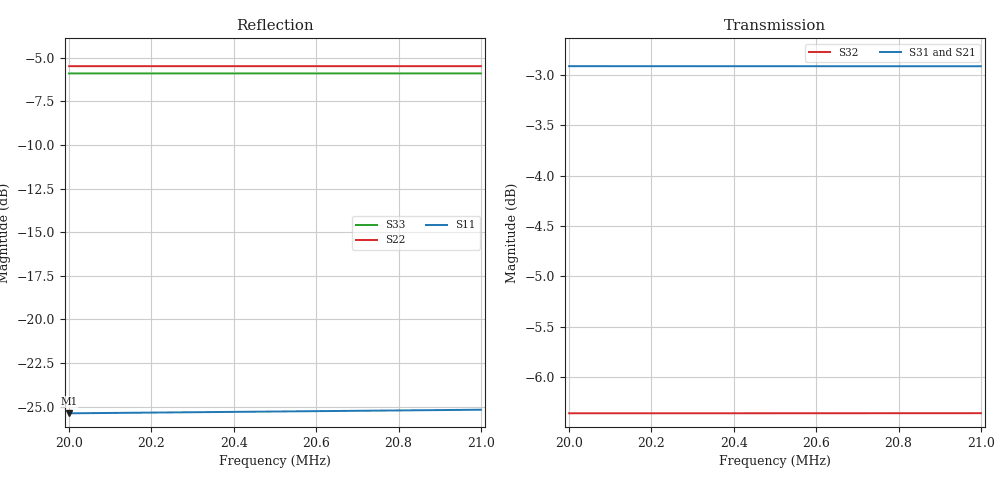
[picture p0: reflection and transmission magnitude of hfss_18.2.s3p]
! Touchstone file exported from HFSS 2018.2.0
!  File:  test.aedt
!  Generated:  4:09:18  mai 02, 2019
!  Design:  test
!  Project:  test
!  Setup:  Setup1
!  Solution:  Sweep
!Data is not renormalized
# GHZ S MA
! Modal data exported
! Port[1] = 1:1
! Port[2] = 2:1
! Port[3] = 3:1
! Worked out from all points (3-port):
!   11 points, 20 MHz to 21 MHz, reference per port
!   strongest paths, dB at 20 MHz, 20.2 MHz, 20.5 MHz, 20.8 MHz, 21 MHz:
!     S31: -2.9, -2.9, -2.9, -2.9, -2.9
!     S21: -3.1, -3.1, -3.1, -3.1, -3.1
!     S32: -6.4, -6.4, -6.4, -6.4, -6.4
!   lowest |S11| = -25.4 dB at 20 MHz (marker M1), VSWR 1.11
!   |S11| at or under -10 dB: start of sweep to end of sweep
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0.02  0.0538 -57.1  0.6968 -9.9  0.7151 -10.1
      0.6968 -9.9  0.5321 175.3  0.4808 -9.1
      0.7151 -10.1  0.4808 -9.1  0.5073 175.2
0.0201  0.05393 -57.4  0.6968 -9.9  0.7151 -10.1
        0.6968 -9.9  0.5321 175.3  0.4808 -9.2
        0.7151 -10.1  0.4808 -9.2  0.5073 175.1
0.0202  0.05406 -57.6  0.6968 -10.0  0.7151 -10.2
        0.6968 -10.0  0.5321 175.3  0.4808 -9.2
        0.7151 -10.2  0.4808 -9.2  0.5073 175.1
0.0203  0.05419 -57.8  0.6968 -10.0  0.7151 -10.2
        0.6968 -10.0  0.5321 175.2  0.4808 -9.3
        0.7151 -10.2  0.4808 -9.3  0.5073 175.1
0.0204  0.05432 -58.0  0.6968 -10.1  0.7151 -10.3
        0.6968 -10.1  0.5321 175.2  0.4808 -9.3
        0.7151 -10.3  0.4808 -9.3  0.5073 175.1
0.0205  0.05445 -58.2  0.6968 -10.1  0.7151 -10.3
        0.6968 -10.1  0.5321 175.2  0.4808 -9.4
        0.7151 -10.3  0.4808 -9.4  0.5073 175.0
0.0206  0.05458 -58.4  0.6968 -10.2  0.7151 -10.4
        0.6968 -10.2  0.5321 175.2  0.4808 -9.4
        0.7151 -10.4  0.4808 -9.4  0.5073 175.0
0.0207  0.05471 -58.6  0.6968 -10.2  0.7151 -10.4
        0.6968 -10.2  0.5321 175.2  0.4808 -9.4
        0.7151 -10.4  0.4808 -9.4  0.5073 175.0
0.0208  0.05484 -58.9  0.6968 -10.3  0.715 -10.5
        0.6968 -10.3  0.5321 175.1  0.4808 -9.5
        0.715 -10.5  0.4808 -9.5  0.5073 175.0
0.021  0.0551 -59.3  0.6968 -10.4  0.715 -10.6
       0.6968 -10.4  0.5321 175.1  0.4809 -9.6
       0.715 -10.6  0.4809 -9.6  0.5073 174.9
